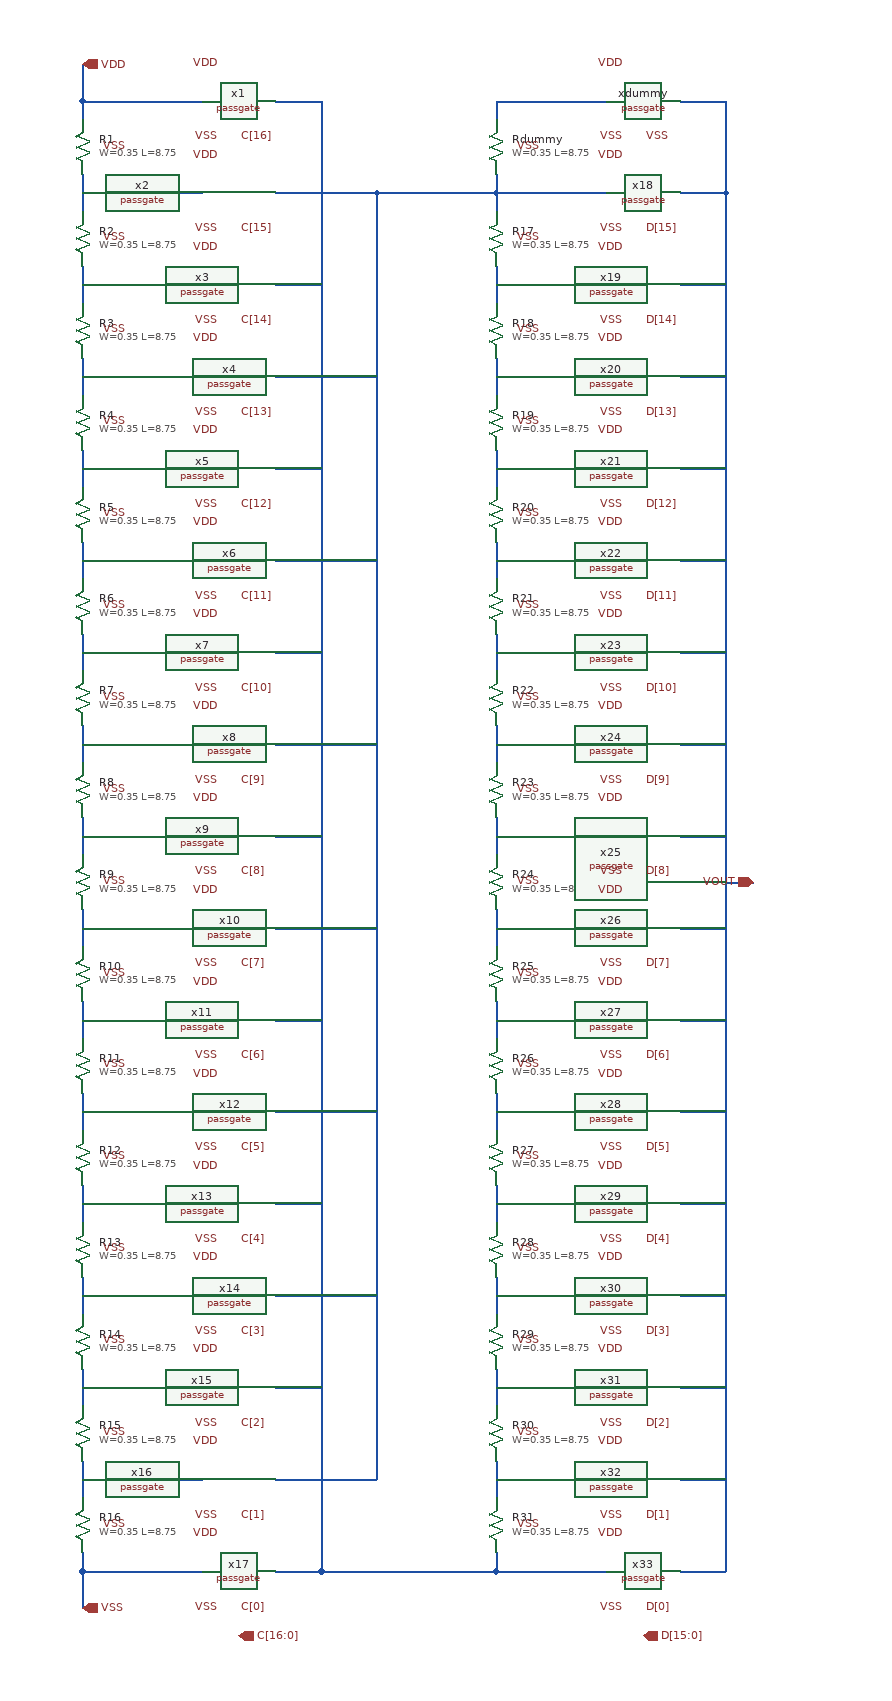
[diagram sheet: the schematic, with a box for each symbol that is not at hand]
v {xschem version=3.4.6 file_version=1.2}
G {}
K {}
V {}
S {}
E {}
N 340 -1750 340 -1730 {lab=VDD}
N 340 -1670 340 -1630 {lab=#net1}
N 340 -1570 340 -1530 {lab=#net2}
N 340 -1470 340 -1430 {lab=#net3}
N 340 -1370 340 -1330 {lab=#net4}
N 340 -1270 340 -1230 {lab=#net5}
N 340 -1170 340 -1130 {lab=#net6}
N 340 -1070 340 -1030 {lab=#net7}
N 340 -970 340 -930 {lab=#net8}
N 340 -870 340 -830 {lab=#net9}
N 340 -770 340 -730 {lab=#net10}
N 340 -670 340 -630 {lab=#net11}
N 340 -570 340 -530 {lab=#net12}
N 340 -470 340 -430 {lab=#net13}
N 340 -370 340 -330 {lab=#net14}
N 340 -270 340 -230 {lab=#net15}
N 340 -170 340 -150 {lab=VSS}
N 340 -1790 340 -1750 {lab=VDD}
N 340 -1750 470 -1750 {lab=VDD}
N 340 -1650 470 -1650 {lab=#net1}
N 340 -1550 470 -1550 {lab=#net2}
N 340 -1450 470 -1450 {lab=#net3}
N 340 -1350 470 -1350 {lab=#net4}
N 340 -1250 470 -1250 {lab=#net5}
N 340 -1150 470 -1150 {lab=#net6}
N 340 -1050 470 -1050 {lab=#net7}
N 340 -950 470 -950 {lab=#net8}
N 340 -850 470 -850 {lab=#net9}
N 340 -750 470 -750 {lab=#net10}
N 340 -650 470 -650 {lab=#net11}
N 340 -550 470 -550 {lab=#net12}
N 340 -450 470 -450 {lab=#net13}
N 340 -350 470 -350 {lab=#net14}
N 340 -250 470 -250 {lab=#net15}
N 340 -150 470 -150 {lab=VSS}
N 340 -150 340 -110 {lab=VSS}
N 550 -1750 600 -1750 {lab=#net16}
N 550 -1550 600 -1550 {lab=#net16}
N 550 -1350 600 -1350 {lab=#net16}
N 550 -1150 600 -1150 {lab=#net16}
N 550 -950 600 -950 {lab=#net16}
N 550 -750 600 -750 {lab=#net16}
N 550 -550 600 -550 {lab=#net16}
N 550 -350 600 -350 {lab=#net16}
N 550 -150 600 -150 {lab=#net16}
N 600 -1750 600 -150 {lab=#net16}
N 600 -150 790 -150 {lab=#net16}
N 550 -1650 660 -1650 {lab=#net17}
N 550 -1450 660 -1450 {lab=#net17}
N 550 -1250 660 -1250 {lab=#net17}
N 550 -1050 660 -1050 {lab=#net17}
N 550 -850 660 -850 {lab=#net17}
N 550 -650 660 -650 {lab=#net17}
N 550 -450 660 -450 {lab=#net17}
N 550 -250 660 -250 {lab=#net17}
N 660 -1650 660 -250 {lab=#net17}
N 660 -1650 790 -1650 {lab=#net17}
N 790 -1650 790 -1630 {lab=#net17}
N 790 -1570 790 -1530 {lab=#net18}
N 790 -1470 790 -1430 {lab=#net19}
N 790 -1370 790 -1330 {lab=#net20}
N 790 -1270 790 -1230 {lab=#net21}
N 790 -1170 790 -1130 {lab=#net22}
N 790 -1070 790 -1030 {lab=#net23}
N 790 -970 790 -930 {lab=#net24}
N 790 -870 790 -830 {lab=#net25}
N 790 -770 790 -730 {lab=#net26}
N 790 -670 790 -630 {lab=#net27}
N 790 -570 790 -530 {lab=#net28}
N 790 -470 790 -430 {lab=#net29}
N 790 -370 790 -330 {lab=#net30}
N 790 -270 790 -230 {lab=#net31}
N 790 -170 790 -150 {lab=#net16}
N 990 -1650 1040 -1650 {lab=VOUT}
N 790 -1650 910 -1650 {lab=#net17}
N 790 -1550 910 -1550 {lab=#net18}
N 790 -1450 910 -1450 {lab=#net19}
N 790 -1350 910 -1350 {lab=#net20}
N 790 -1250 910 -1250 {lab=#net21}
N 790 -1150 910 -1150 {lab=#net22}
N 790 -1050 910 -1050 {lab=#net23}
N 790 -950 910 -950 {lab=#net24}
N 790 -850 910 -850 {lab=#net25}
N 790 -750 910 -750 {lab=#net26}
N 790 -650 910 -650 {lab=#net27}
N 790 -550 910 -550 {lab=#net28}
N 790 -450 910 -450 {lab=#net29}
N 790 -350 910 -350 {lab=#net30}
N 790 -250 910 -250 {lab=#net31}
N 790 -150 910 -150 {lab=#net16}
N 990 -1550 1040 -1550 {lab=VOUT}
N 990 -1450 1040 -1450 {lab=VOUT}
N 990 -1350 1040 -1350 {lab=VOUT}
N 990 -1250 1040 -1250 {lab=VOUT}
N 990 -1150 1040 -1150 {lab=VOUT}
N 990 -1050 1040 -1050 {lab=VOUT}
N 990 -950 1040 -950 {lab=VOUT}
N 990 -850 1040 -850 {lab=VOUT}
N 990 -750 1040 -750 {lab=VOUT}
N 990 -650 1040 -650 {lab=VOUT}
N 990 -550 1040 -550 {lab=VOUT}
N 990 -450 1040 -450 {lab=VOUT}
N 990 -350 1040 -350 {lab=VOUT}
N 990 -250 1040 -250 {lab=VOUT}
N 990 -150 1040 -150 {lab=VOUT}
N 1040 -1650 1040 -150 {lab=VOUT}
N 1040 -900 1070 -900 {lab=VOUT}
N 790 -1670 790 -1650 {lab=#net17}
N 790 -1750 790 -1730 {lab=#net32}
N 790 -1750 910 -1750 {lab=#net32}
N 990 -1750 1040 -1750 {lab=VOUT}
N 1040 -1750 1040 -1650 {lab=VOUT}
C {sky130_fd_pr/res_xhigh_po_0p35.sym} 340 -1700 2 0 {name=R1
W=0.35
L=8.75
model=res_xhigh_po_0p35
spiceprefix=X
mult=1}
C {sky130_fd_pr/res_xhigh_po_0p35.sym} 340 -1600 2 0 {name=R2
W=0.35
L=8.75
model=res_xhigh_po_0p35
spiceprefix=X
mult=1}
C {sky130_fd_pr/res_xhigh_po_0p35.sym} 340 -1500 2 0 {name=R3
W=0.35
L=8.75
model=res_xhigh_po_0p35
spiceprefix=X
mult=1}
C {sky130_fd_pr/res_xhigh_po_0p35.sym} 340 -1400 2 0 {name=R4
W=0.35
L=8.75
model=res_xhigh_po_0p35
spiceprefix=X
mult=1}
C {sky130_fd_pr/res_xhigh_po_0p35.sym} 340 -1300 2 0 {name=R5
W=0.35
L=8.75
model=res_xhigh_po_0p35
spiceprefix=X
mult=1}
C {sky130_fd_pr/res_xhigh_po_0p35.sym} 340 -1200 2 0 {name=R6
W=0.35
L=8.75
model=res_xhigh_po_0p35
spiceprefix=X
mult=1}
C {sky130_fd_pr/res_xhigh_po_0p35.sym} 340 -1100 2 0 {name=R7
W=0.35
L=8.75
model=res_xhigh_po_0p35
spiceprefix=X
mult=1}
C {sky130_fd_pr/res_xhigh_po_0p35.sym} 340 -1000 2 0 {name=R8
W=0.35
L=8.75
model=res_xhigh_po_0p35
spiceprefix=X
mult=1}
C {sky130_fd_pr/res_xhigh_po_0p35.sym} 340 -900 2 0 {name=R9
W=0.35
L=8.75
model=res_xhigh_po_0p35
spiceprefix=X
mult=1}
C {sky130_fd_pr/res_xhigh_po_0p35.sym} 340 -800 2 0 {name=R10
W=0.35
L=8.75
model=res_xhigh_po_0p35
spiceprefix=X
mult=1}
C {sky130_fd_pr/res_xhigh_po_0p35.sym} 340 -700 2 0 {name=R11
W=0.35
L=8.75
model=res_xhigh_po_0p35
spiceprefix=X
mult=1}
C {sky130_fd_pr/res_xhigh_po_0p35.sym} 340 -600 2 0 {name=R12
W=0.35
L=8.75
model=res_xhigh_po_0p35
spiceprefix=X
mult=1}
C {sky130_fd_pr/res_xhigh_po_0p35.sym} 340 -500 2 0 {name=R13
W=0.35
L=8.75
model=res_xhigh_po_0p35
spiceprefix=X
mult=1}
C {sky130_fd_pr/res_xhigh_po_0p35.sym} 340 -400 2 0 {name=R14
W=0.35
L=8.75
model=res_xhigh_po_0p35
spiceprefix=X
mult=1}
C {sky130_fd_pr/res_xhigh_po_0p35.sym} 340 -300 2 0 {name=R15
W=0.35
L=8.75
model=res_xhigh_po_0p35
spiceprefix=X
mult=1}
C {sky130_fd_pr/res_xhigh_po_0p35.sym} 340 -200 2 0 {name=R16
W=0.35
L=8.75
model=res_xhigh_po_0p35
spiceprefix=X
mult=1}
C {passgate.sym} 510 -1750 0 0 {name=x1}
C {devices/lab_pin.sym} 360 -1700 0 1 {name=p2 sig_type=std_logic lab=VSS}
C {devices/lab_pin.sym} 360 -1600 0 1 {name=p4 sig_type=std_logic lab=VSS}
C {devices/lab_pin.sym} 360 -1500 0 1 {name=p5 sig_type=std_logic lab=VSS}
C {devices/lab_pin.sym} 360 -1400 0 1 {name=p6 sig_type=std_logic lab=VSS}
C {devices/lab_pin.sym} 360 -1300 0 1 {name=p8 sig_type=std_logic lab=VSS}
C {devices/lab_pin.sym} 360 -1200 0 1 {name=p9 sig_type=std_logic lab=VSS}
C {devices/lab_pin.sym} 360 -1100 0 1 {name=p10 sig_type=std_logic lab=VSS}
C {devices/lab_pin.sym} 360 -1000 0 1 {name=p11 sig_type=std_logic lab=VSS}
C {devices/lab_pin.sym} 360 -900 0 1 {name=p12 sig_type=std_logic lab=VSS}
C {devices/lab_pin.sym} 360 -800 0 1 {name=p13 sig_type=std_logic lab=VSS}
C {devices/lab_pin.sym} 360 -700 0 1 {name=p14 sig_type=std_logic lab=VSS}
C {devices/lab_pin.sym} 360 -600 0 1 {name=p15 sig_type=std_logic lab=VSS}
C {devices/lab_pin.sym} 360 -500 0 1 {name=p16 sig_type=std_logic lab=VSS}
C {devices/lab_pin.sym} 360 -400 0 1 {name=p17 sig_type=std_logic lab=VSS}
C {devices/lab_pin.sym} 360 -300 0 1 {name=p18 sig_type=std_logic lab=VSS}
C {devices/lab_pin.sym} 360 -200 0 1 {name=p19 sig_type=std_logic lab=VSS}
C {devices/lab_pin.sym} 490 -1790 0 0 {name=p20 sig_type=std_logic lab=VDD}
C {devices/lab_pin.sym} 490 -1710 0 0 {name=p21 sig_type=std_logic lab=VSS}
C {passgate.sym} 510 -1650 0 0 {name=x2}
C {devices/lab_pin.sym} 490 -1690 0 0 {name=p22 sig_type=std_logic lab=VDD}
C {devices/lab_pin.sym} 490 -1610 0 0 {name=p23 sig_type=std_logic lab=VSS}
C {passgate.sym} 510 -1550 0 0 {name=x3}
C {devices/lab_pin.sym} 490 -1590 0 0 {name=p24 sig_type=std_logic lab=VDD}
C {devices/lab_pin.sym} 490 -1510 0 0 {name=p25 sig_type=std_logic lab=VSS}
C {passgate.sym} 510 -1450 0 0 {name=x4}
C {devices/lab_pin.sym} 490 -1490 0 0 {name=p26 sig_type=std_logic lab=VDD}
C {devices/lab_pin.sym} 490 -1410 0 0 {name=p27 sig_type=std_logic lab=VSS}
C {passgate.sym} 510 -1350 0 0 {name=x5}
C {devices/lab_pin.sym} 490 -1390 0 0 {name=p28 sig_type=std_logic lab=VDD}
C {devices/lab_pin.sym} 490 -1310 0 0 {name=p29 sig_type=std_logic lab=VSS}
C {passgate.sym} 510 -1250 0 0 {name=x6}
C {devices/lab_pin.sym} 490 -1290 0 0 {name=p30 sig_type=std_logic lab=VDD}
C {devices/lab_pin.sym} 490 -1210 0 0 {name=p31 sig_type=std_logic lab=VSS}
C {passgate.sym} 510 -1150 0 0 {name=x7}
C {devices/lab_pin.sym} 490 -1190 0 0 {name=p32 sig_type=std_logic lab=VDD}
C {devices/lab_pin.sym} 490 -1110 0 0 {name=p33 sig_type=std_logic lab=VSS}
C {passgate.sym} 510 -1050 0 0 {name=x8}
C {devices/lab_pin.sym} 490 -1090 0 0 {name=p34 sig_type=std_logic lab=VDD}
C {devices/lab_pin.sym} 490 -1010 0 0 {name=p35 sig_type=std_logic lab=VSS}
C {passgate.sym} 510 -950 0 0 {name=x9}
C {devices/lab_pin.sym} 490 -990 0 0 {name=p36 sig_type=std_logic lab=VDD}
C {devices/lab_pin.sym} 490 -910 0 0 {name=p37 sig_type=std_logic lab=VSS}
C {passgate.sym} 510 -850 0 0 {name=x10}
C {devices/lab_pin.sym} 490 -890 0 0 {name=p38 sig_type=std_logic lab=VDD}
C {devices/lab_pin.sym} 490 -810 0 0 {name=p39 sig_type=std_logic lab=VSS}
C {passgate.sym} 510 -750 0 0 {name=x11}
C {devices/lab_pin.sym} 490 -790 0 0 {name=p40 sig_type=std_logic lab=VDD}
C {devices/lab_pin.sym} 490 -710 0 0 {name=p41 sig_type=std_logic lab=VSS}
C {passgate.sym} 510 -650 0 0 {name=x12}
C {devices/lab_pin.sym} 490 -690 0 0 {name=p42 sig_type=std_logic lab=VDD}
C {devices/lab_pin.sym} 490 -610 0 0 {name=p43 sig_type=std_logic lab=VSS}
C {passgate.sym} 510 -550 0 0 {name=x13}
C {devices/lab_pin.sym} 490 -590 0 0 {name=p44 sig_type=std_logic lab=VDD}
C {devices/lab_pin.sym} 490 -510 0 0 {name=p45 sig_type=std_logic lab=VSS}
C {passgate.sym} 510 -450 0 0 {name=x14}
C {devices/lab_pin.sym} 490 -490 0 0 {name=p46 sig_type=std_logic lab=VDD}
C {devices/lab_pin.sym} 490 -410 0 0 {name=p47 sig_type=std_logic lab=VSS}
C {passgate.sym} 510 -350 0 0 {name=x15}
C {devices/lab_pin.sym} 490 -390 0 0 {name=p48 sig_type=std_logic lab=VDD}
C {devices/lab_pin.sym} 490 -310 0 0 {name=p49 sig_type=std_logic lab=VSS}
C {passgate.sym} 510 -250 0 0 {name=x16}
C {devices/lab_pin.sym} 490 -290 0 0 {name=p50 sig_type=std_logic lab=VDD}
C {devices/lab_pin.sym} 490 -210 0 0 {name=p51 sig_type=std_logic lab=VSS}
C {passgate.sym} 510 -150 0 0 {name=x17}
C {devices/lab_pin.sym} 490 -190 0 0 {name=p52 sig_type=std_logic lab=VDD}
C {devices/lab_pin.sym} 490 -110 0 0 {name=p53 sig_type=std_logic lab=VSS}
C {sky130_fd_pr/res_xhigh_po_0p35.sym} 790 -1600 2 0 {name=R17
W=0.35
L=8.75
model=res_xhigh_po_0p35
spiceprefix=X
mult=1}
C {sky130_fd_pr/res_xhigh_po_0p35.sym} 790 -1500 2 0 {name=R18
W=0.35
L=8.75
model=res_xhigh_po_0p35
spiceprefix=X
mult=1}
C {sky130_fd_pr/res_xhigh_po_0p35.sym} 790 -1400 2 0 {name=R19
W=0.35
L=8.75
model=res_xhigh_po_0p35
spiceprefix=X
mult=1}
C {sky130_fd_pr/res_xhigh_po_0p35.sym} 790 -1300 2 0 {name=R20
W=0.35
L=8.75
model=res_xhigh_po_0p35
spiceprefix=X
mult=1}
C {sky130_fd_pr/res_xhigh_po_0p35.sym} 790 -1200 2 0 {name=R21
W=0.35
L=8.75
model=res_xhigh_po_0p35
spiceprefix=X
mult=1}
C {sky130_fd_pr/res_xhigh_po_0p35.sym} 790 -1100 2 0 {name=R22
W=0.35
L=8.75
model=res_xhigh_po_0p35
spiceprefix=X
mult=1}
C {sky130_fd_pr/res_xhigh_po_0p35.sym} 790 -1000 2 0 {name=R23
W=0.35
L=8.75
model=res_xhigh_po_0p35
spiceprefix=X
mult=1}
C {sky130_fd_pr/res_xhigh_po_0p35.sym} 790 -900 2 0 {name=R24
W=0.35
L=8.75
model=res_xhigh_po_0p35
spiceprefix=X
mult=1}
C {sky130_fd_pr/res_xhigh_po_0p35.sym} 790 -800 2 0 {name=R25
W=0.35
L=8.75
model=res_xhigh_po_0p35
spiceprefix=X
mult=1}
C {sky130_fd_pr/res_xhigh_po_0p35.sym} 790 -700 2 0 {name=R26
W=0.35
L=8.75
model=res_xhigh_po_0p35
spiceprefix=X
mult=1}
C {sky130_fd_pr/res_xhigh_po_0p35.sym} 790 -600 2 0 {name=R27
W=0.35
L=8.75
model=res_xhigh_po_0p35
spiceprefix=X
mult=1}
C {sky130_fd_pr/res_xhigh_po_0p35.sym} 790 -500 2 0 {name=R28
W=0.35
L=8.75
model=res_xhigh_po_0p35
spiceprefix=X
mult=1}
C {sky130_fd_pr/res_xhigh_po_0p35.sym} 790 -400 2 0 {name=R29
W=0.35
L=8.75
model=res_xhigh_po_0p35
spiceprefix=X
mult=1}
C {sky130_fd_pr/res_xhigh_po_0p35.sym} 790 -300 2 0 {name=R30
W=0.35
L=8.75
model=res_xhigh_po_0p35
spiceprefix=X
mult=1}
C {sky130_fd_pr/res_xhigh_po_0p35.sym} 790 -200 2 0 {name=R31
W=0.35
L=8.75
model=res_xhigh_po_0p35
spiceprefix=X
mult=1}
C {devices/lab_pin.sym} 810 -1600 0 1 {name=p55 sig_type=std_logic lab=VSS}
C {devices/lab_pin.sym} 810 -1500 0 1 {name=p56 sig_type=std_logic lab=VSS}
C {devices/lab_pin.sym} 810 -1400 0 1 {name=p57 sig_type=std_logic lab=VSS}
C {devices/lab_pin.sym} 810 -1300 0 1 {name=p58 sig_type=std_logic lab=VSS}
C {devices/lab_pin.sym} 810 -1200 0 1 {name=p59 sig_type=std_logic lab=VSS}
C {devices/lab_pin.sym} 810 -1100 0 1 {name=p60 sig_type=std_logic lab=VSS}
C {devices/lab_pin.sym} 810 -1000 0 1 {name=p61 sig_type=std_logic lab=VSS}
C {devices/lab_pin.sym} 810 -900 0 1 {name=p62 sig_type=std_logic lab=VSS}
C {devices/lab_pin.sym} 810 -800 0 1 {name=p63 sig_type=std_logic lab=VSS}
C {devices/lab_pin.sym} 810 -700 0 1 {name=p64 sig_type=std_logic lab=VSS}
C {devices/lab_pin.sym} 810 -600 0 1 {name=p65 sig_type=std_logic lab=VSS}
C {devices/lab_pin.sym} 810 -500 0 1 {name=p66 sig_type=std_logic lab=VSS}
C {devices/lab_pin.sym} 810 -400 0 1 {name=p67 sig_type=std_logic lab=VSS}
C {devices/lab_pin.sym} 810 -300 0 1 {name=p68 sig_type=std_logic lab=VSS}
C {devices/lab_pin.sym} 810 -200 0 1 {name=p69 sig_type=std_logic lab=VSS}
C {passgate.sym} 950 -1650 0 0 {name=x18}
C {devices/lab_pin.sym} 930 -1690 0 0 {name=p54 sig_type=std_logic lab=VDD}
C {devices/lab_pin.sym} 930 -1610 0 0 {name=p70 sig_type=std_logic lab=VSS}
C {passgate.sym} 950 -1550 0 0 {name=x19}
C {devices/lab_pin.sym} 930 -1590 0 0 {name=p71 sig_type=std_logic lab=VDD}
C {devices/lab_pin.sym} 930 -1510 0 0 {name=p72 sig_type=std_logic lab=VSS}
C {passgate.sym} 950 -1450 0 0 {name=x20}
C {devices/lab_pin.sym} 930 -1490 0 0 {name=p73 sig_type=std_logic lab=VDD}
C {devices/lab_pin.sym} 930 -1410 0 0 {name=p74 sig_type=std_logic lab=VSS}
C {passgate.sym} 950 -1350 0 0 {name=x21}
C {devices/lab_pin.sym} 930 -1390 0 0 {name=p75 sig_type=std_logic lab=VDD}
C {devices/lab_pin.sym} 930 -1310 0 0 {name=p76 sig_type=std_logic lab=VSS}
C {passgate.sym} 950 -1250 0 0 {name=x22}
C {devices/lab_pin.sym} 930 -1290 0 0 {name=p77 sig_type=std_logic lab=VDD}
C {devices/lab_pin.sym} 930 -1210 0 0 {name=p78 sig_type=std_logic lab=VSS}
C {passgate.sym} 950 -1150 0 0 {name=x23}
C {devices/lab_pin.sym} 930 -1190 0 0 {name=p79 sig_type=std_logic lab=VDD}
C {devices/lab_pin.sym} 930 -1110 0 0 {name=p80 sig_type=std_logic lab=VSS}
C {passgate.sym} 950 -1050 0 0 {name=x24}
C {devices/lab_pin.sym} 930 -1090 0 0 {name=p81 sig_type=std_logic lab=VDD}
C {devices/lab_pin.sym} 930 -1010 0 0 {name=p82 sig_type=std_logic lab=VSS}
C {passgate.sym} 950 -950 0 0 {name=x25}
C {devices/lab_pin.sym} 930 -990 0 0 {name=p83 sig_type=std_logic lab=VDD}
C {devices/lab_pin.sym} 930 -910 0 0 {name=p84 sig_type=std_logic lab=VSS}
C {passgate.sym} 950 -850 0 0 {name=x26}
C {devices/lab_pin.sym} 930 -890 0 0 {name=p85 sig_type=std_logic lab=VDD}
C {devices/lab_pin.sym} 930 -810 0 0 {name=p86 sig_type=std_logic lab=VSS}
C {passgate.sym} 950 -750 0 0 {name=x27}
C {devices/lab_pin.sym} 930 -790 0 0 {name=p87 sig_type=std_logic lab=VDD}
C {devices/lab_pin.sym} 930 -710 0 0 {name=p88 sig_type=std_logic lab=VSS}
C {passgate.sym} 950 -650 0 0 {name=x28}
C {devices/lab_pin.sym} 930 -690 0 0 {name=p89 sig_type=std_logic lab=VDD}
C {devices/lab_pin.sym} 930 -610 0 0 {name=p90 sig_type=std_logic lab=VSS}
C {passgate.sym} 950 -550 0 0 {name=x29}
C {devices/lab_pin.sym} 930 -590 0 0 {name=p91 sig_type=std_logic lab=VDD}
C {devices/lab_pin.sym} 930 -510 0 0 {name=p92 sig_type=std_logic lab=VSS}
C {passgate.sym} 950 -450 0 0 {name=x30}
C {devices/lab_pin.sym} 930 -490 0 0 {name=p93 sig_type=std_logic lab=VDD}
C {devices/lab_pin.sym} 930 -410 0 0 {name=p94 sig_type=std_logic lab=VSS}
C {passgate.sym} 950 -350 0 0 {name=x31}
C {devices/lab_pin.sym} 930 -390 0 0 {name=p95 sig_type=std_logic lab=VDD}
C {devices/lab_pin.sym} 930 -310 0 0 {name=p96 sig_type=std_logic lab=VSS}
C {passgate.sym} 950 -250 0 0 {name=x32}
C {devices/lab_pin.sym} 930 -290 0 0 {name=p97 sig_type=std_logic lab=VDD}
C {devices/lab_pin.sym} 930 -210 0 0 {name=p98 sig_type=std_logic lab=VSS}
C {passgate.sym} 950 -150 0 0 {name=x33}
C {devices/lab_pin.sym} 930 -190 0 0 {name=p99 sig_type=std_logic lab=VDD}
C {devices/lab_pin.sym} 930 -110 0 0 {name=p100 sig_type=std_logic lab=VSS}
C {devices/iopin.sym} 340 -110 0 1 {name=p102 lab=VSS}
C {devices/iopin.sym} 340 -1790 0 1 {name=p3 lab=VDD}
C {devices/iopin.sym} 1070 -900 0 0 {name=p7 lab=VOUT}
C {devices/lab_pin.sym} 510 -110 0 1 {name=p101 lab=C[0]}
C {devices/lab_pin.sym} 510 -210 0 1 {name=p103 lab=C[1]}
C {devices/lab_pin.sym} 510 -310 0 1 {name=p104 lab=C[2]}
C {devices/lab_pin.sym} 510 -410 0 1 {name=p105 lab=C[3]}
C {devices/lab_pin.sym} 510 -510 0 1 {name=p106 lab=C[4]}
C {devices/lab_pin.sym} 510 -610 0 1 {name=p107 lab=C[5]}
C {devices/lab_pin.sym} 510 -710 0 1 {name=p108 lab=C[6]}
C {devices/lab_pin.sym} 510 -810 0 1 {name=p109 lab=C[7]}
C {devices/lab_pin.sym} 510 -910 0 1 {name=p110 lab=C[8]}
C {devices/lab_pin.sym} 510 -1010 0 1 {name=p111 lab=C[9]}
C {devices/lab_pin.sym} 510 -1110 0 1 {name=p112 lab=C[10]}
C {devices/lab_pin.sym} 510 -1210 0 1 {name=p113 lab=C[11]}
C {devices/lab_pin.sym} 510 -1310 0 1 {name=p114 lab=C[12]}
C {devices/lab_pin.sym} 510 -1410 0 1 {name=p115 lab=C[13]}
C {devices/lab_pin.sym} 510 -1510 0 1 {name=p116 lab=C[14]}
C {devices/lab_pin.sym} 510 -1610 0 1 {name=p117 lab=C[15]}
C {devices/lab_pin.sym} 510 -1710 0 1 {name=p118 lab=C[16]}
C {devices/lab_pin.sym} 950 -110 0 1 {name=p119 lab=D[0]}
C {devices/lab_pin.sym} 950 -210 0 1 {name=p121 lab=D[1]}
C {devices/lab_pin.sym} 950 -310 0 1 {name=p122 lab=D[2]}
C {devices/lab_pin.sym} 950 -410 0 1 {name=p123 lab=D[3]}
C {devices/lab_pin.sym} 950 -510 0 1 {name=p124 lab=D[4]}
C {devices/lab_pin.sym} 950 -610 0 1 {name=p125 lab=D[5]}
C {devices/lab_pin.sym} 950 -710 0 1 {name=p126 lab=D[6]}
C {devices/lab_pin.sym} 950 -810 0 1 {name=p127 lab=D[7]}
C {devices/lab_pin.sym} 950 -910 0 1 {name=p128 lab=D[8]}
C {devices/lab_pin.sym} 950 -1010 0 1 {name=p129 lab=D[9]}
C {devices/lab_pin.sym} 950 -1110 0 1 {name=p130 lab=D[10]}
C {devices/lab_pin.sym} 950 -1210 0 1 {name=p131 lab=D[11]}
C {devices/lab_pin.sym} 950 -1310 0 1 {name=p132 lab=D[12]}
C {devices/lab_pin.sym} 950 -1410 0 1 {name=p133 lab=D[13]}
C {devices/lab_pin.sym} 950 -1510 0 1 {name=p134 lab=D[14]}
C {devices/lab_pin.sym} 950 -1610 0 1 {name=p135 lab=D[15]}
C {devices/ipin.sym} 510 -80 2 1 {name=p1 lab=C[16:0]}
C {devices/ipin.sym} 950 -80 2 1 {name=p140 lab=D[15:0]}
C {sky130_fd_pr/res_xhigh_po_0p35.sym} 790 -1700 2 0 {name=Rdummy
W=0.35
L=8.75
model=res_xhigh_po_0p35
spiceprefix=X
mult=1}
C {passgate.sym} 950 -1750 0 0 {name=xdummy}
C {devices/lab_pin.sym} 930 -1790 0 0 {name=p120 sig_type=std_logic lab=VDD}
C {devices/lab_pin.sym} 930 -1710 0 0 {name=p136 sig_type=std_logic lab=VSS}
C {devices/lab_pin.sym} 950 -1710 0 1 {name=p137 lab=VSS}
C {devices/lab_pin.sym} 810 -1700 0 1 {name=p138 sig_type=std_logic lab=VSS}
